###############################################################
#  Generated by:      Cadence Innovus 21.14-s109_1
#  OS:                Linux x86_64(Host ID caen-vnc-mi02.engin.umich.edu)
#  Generated on:      Mon Mar 27 17:20:06 2023
#  Design:            wb_controller
#  Command:           write_lef_abstract /afs/umich.edu/class/eecs627/w23/students/yihengfu/HW2/apr/data/wb_controller.lef -specifyTopLayer 4 -stripePin -PGpinLayers 4
###############################################################

VERSION 5.8 ;

BUSBITCHARS "[]" ;
DIVIDERCHAR "/" ;

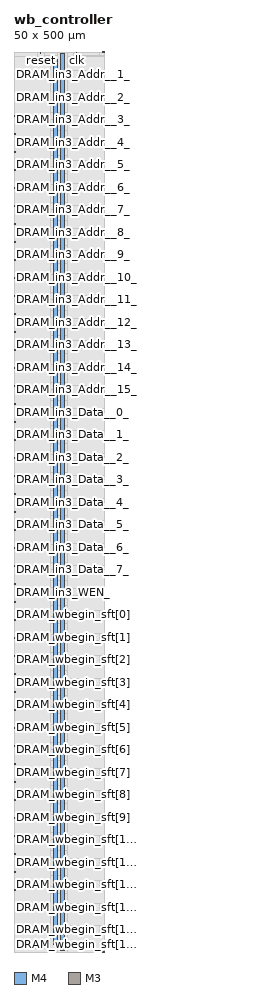
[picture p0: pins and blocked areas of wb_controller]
MACRO wb_controller
  CLASS BLOCK ;
  SIZE 50.000000 BY 500.000000 ;
  FOREIGN wb_controller 0.000000 0.000000 ;
  ORIGIN 0 0 ;
  SYMMETRY X Y R90 ;
  PIN clk
    DIRECTION INPUT ;
    USE SIGNAL ;
    ANTENNAPARTIALMETALAREA 17.54 LAYER M4  ;
    ANTENNAPARTIALMETALSIDEAREA 0.1766 LAYER M4  ;
    ANTENNAMODEL OXIDE1 ;
    ANTENNAGATEAREA 1.2696 LAYER M4  ;
    ANTENNAMAXAREACAR 90.5344 LAYER M4  ;
    ANTENNAMAXSIDEAREACAR 0.914602 LAYER M4  ;
    ANTENNAMAXCUTCAR 3.47643 LAYER V4  ;
    PORT
      LAYER M4 ;
        RECT 34.700000 499.400000 34.900000 500.000000 ;
    END
  END clk
  PIN reset
    DIRECTION INPUT ;
    USE SIGNAL ;
    ANTENNAPARTIALMETALAREA 20.82 LAYER M4  ;
    ANTENNAPARTIALMETALSIDEAREA 0.2094 LAYER M4  ;
    ANTENNAMODEL OXIDE1 ;
    ANTENNAGATEAREA 3.672 LAYER M4  ;
    ANTENNAMAXAREACAR 40.8088 LAYER M4  ;
    ANTENNAMAXSIDEAREACAR 0.411656 LAYER M4  ;
    ANTENNAMAXCUTCAR 1.46605 LAYER V4  ;
    PORT
      LAYER M4 ;
        RECT 14.700000 499.400000 14.900000 500.000000 ;
    END
  END reset
  PIN DRAM_wbegin_sft[15]
    DIRECTION INPUT ;
    USE SIGNAL ;
    ANTENNAPARTIALMETALAREA 0.16 LAYER M4  ;
    ANTENNAPARTIALMETALSIDEAREA 0.0016 LAYER M4  ;
    ANTENNAMODEL OXIDE1 ;
    ANTENNAGATEAREA 0.1728 LAYER M4  ;
    ANTENNAMAXAREACAR 42.2083 LAYER M4  ;
    ANTENNAMAXSIDEAREACAR 0.435532 LAYER M4  ;
    ANTENNAMAXCUTCAR 1.38889 LAYER V4  ;
    PORT
      LAYER M4 ;
        RECT 49.400000 -0.100000 50.000000 0.100000 ;
    END
  END DRAM_wbegin_sft[15]
  PIN DRAM_wbegin_sft[14]
    DIRECTION INPUT ;
    USE SIGNAL ;
    ANTENNAPARTIALMETALAREA 19.26 LAYER M4  ;
    ANTENNAPARTIALMETALSIDEAREA 0.1934 LAYER M4  ;
    ANTENNAMODEL OXIDE1 ;
    ANTENNAGATEAREA 0.1728 LAYER M4  ;
    ANTENNAMAXAREACAR 134.685 LAYER M4  ;
    ANTENNAMAXSIDEAREACAR 1.35567 LAYER M4  ;
    ANTENNAMAXCUTCAR 0.925926 LAYER V4  ;
    PORT
      LAYER M4 ;
        RECT 49.400000 12.400000 50.000000 12.600000 ;
    END
  END DRAM_wbegin_sft[14]
  PIN DRAM_wbegin_sft[13]
    DIRECTION INPUT ;
    USE SIGNAL ;
    ANTENNAPARTIALMETALAREA 0.2 LAYER M4  ;
    ANTENNAPARTIALMETALSIDEAREA 0.002 LAYER M4  ;
    ANTENNAMODEL OXIDE1 ;
    ANTENNAGATEAREA 0.1728 LAYER M4  ;
    ANTENNAMAXAREACAR 37.1157 LAYER M4  ;
    ANTENNAMAXSIDEAREACAR 0.386921 LAYER M4  ;
    ANTENNAMAXCUTCAR 1.38889 LAYER V4  ;
    PORT
      LAYER M4 ;
        RECT 49.400000 24.900000 50.000000 25.100000 ;
    END
  END DRAM_wbegin_sft[13]
  PIN DRAM_wbegin_sft[12]
    DIRECTION INPUT ;
    USE SIGNAL ;
    ANTENNAPARTIALMETALAREA 0.18 LAYER M4  ;
    ANTENNAPARTIALMETALSIDEAREA 0.0018 LAYER M4  ;
    ANTENNAMODEL OXIDE1 ;
    ANTENNAGATEAREA 0.1728 LAYER M4  ;
    ANTENNAMAXAREACAR 61.0741 LAYER M4  ;
    ANTENNAMAXSIDEAREACAR 0.626505 LAYER M4  ;
    ANTENNAMAXCUTCAR 1.38889 LAYER V4  ;
    PORT
      LAYER M4 ;
        RECT 49.400000 37.400000 50.000000 37.600000 ;
    END
  END DRAM_wbegin_sft[12]
  PIN DRAM_wbegin_sft[11]
    DIRECTION INPUT ;
    USE SIGNAL ;
    ANTENNAPARTIALMETALAREA 0.16 LAYER M4  ;
    ANTENNAPARTIALMETALSIDEAREA 0.0016 LAYER M4  ;
    ANTENNAMODEL OXIDE1 ;
    ANTENNAGATEAREA 0.1728 LAYER M4  ;
    ANTENNAMAXAREACAR 35.2639 LAYER M4  ;
    ANTENNAMAXSIDEAREACAR 0.366088 LAYER M4  ;
    ANTENNAMAXCUTCAR 1.38889 LAYER V4  ;
    PORT
      LAYER M4 ;
        RECT 49.400000 49.900000 50.000000 50.100000 ;
    END
  END DRAM_wbegin_sft[11]
  PIN DRAM_wbegin_sft[10]
    DIRECTION INPUT ;
    USE SIGNAL ;
    ANTENNAPARTIALMETALAREA 0.46 LAYER M4  ;
    ANTENNAPARTIALMETALSIDEAREA 0.0046 LAYER M4  ;
    ANTENNAMODEL OXIDE1 ;
    ANTENNAGATEAREA 0.1728 LAYER M4  ;
    ANTENNAMAXAREACAR 47.4167 LAYER M4  ;
    ANTENNAMAXSIDEAREACAR 0.489931 LAYER M4  ;
    ANTENNAMAXCUTCAR 1.38889 LAYER V4  ;
    PORT
      LAYER M4 ;
        RECT 49.400000 62.400000 50.000000 62.600000 ;
    END
  END DRAM_wbegin_sft[10]
  PIN DRAM_wbegin_sft[9]
    DIRECTION INPUT ;
    USE SIGNAL ;
    ANTENNAPARTIALMETALAREA 0.2 LAYER M4  ;
    ANTENNAPARTIALMETALSIDEAREA 0.002 LAYER M4  ;
    ANTENNAMODEL OXIDE1 ;
    ANTENNAGATEAREA 0.1728 LAYER M4  ;
    ANTENNAMAXAREACAR 91.9769 LAYER M4  ;
    ANTENNAMAXSIDEAREACAR 0.937847 LAYER M4  ;
    ANTENNAMAXCUTCAR 1.38889 LAYER V4  ;
    PORT
      LAYER M4 ;
        RECT 49.400000 74.900000 50.000000 75.100000 ;
    END
  END DRAM_wbegin_sft[9]
  PIN DRAM_wbegin_sft[8]
    DIRECTION INPUT ;
    USE SIGNAL ;
    ANTENNAPARTIALMETALAREA 24.54 LAYER M4  ;
    ANTENNAPARTIALMETALSIDEAREA 0.2466 LAYER M4  ;
    ANTENNAMODEL OXIDE1 ;
    ANTENNAGATEAREA 0.1728 LAYER M4  ;
    ANTENNAMAXAREACAR 277.278 LAYER M4  ;
    ANTENNAMAXSIDEAREACAR 2.78391 LAYER M4  ;
    ANTENNAMAXCUTCAR 0.925926 LAYER V4  ;
    PORT
      LAYER M4 ;
        RECT 49.400000 87.400000 50.000000 87.600000 ;
    END
  END DRAM_wbegin_sft[8]
  PIN DRAM_wbegin_sft[7]
    DIRECTION INPUT ;
    USE SIGNAL ;
    ANTENNAPARTIALMETALAREA 0.16 LAYER M4  ;
    ANTENNAPARTIALMETALSIDEAREA 0.0016 LAYER M4  ;
    ANTENNAMODEL OXIDE1 ;
    ANTENNAGATEAREA 0.1728 LAYER M4  ;
    ANTENNAMAXAREACAR 72.7639 LAYER M4  ;
    ANTENNAMAXSIDEAREACAR 0.741088 LAYER M4  ;
    ANTENNAMAXCUTCAR 1.38889 LAYER V4  ;
    PORT
      LAYER M4 ;
        RECT 49.400000 99.900000 50.000000 100.100000 ;
    END
  END DRAM_wbegin_sft[7]
  PIN DRAM_wbegin_sft[6]
    DIRECTION INPUT ;
    USE SIGNAL ;
    ANTENNAPARTIALMETALAREA 0.14 LAYER M4  ;
    ANTENNAPARTIALMETALSIDEAREA 0.0014 LAYER M4  ;
    ANTENNAMODEL OXIDE1 ;
    ANTENNAGATEAREA 0.1728 LAYER M4  ;
    ANTENNAMAXAREACAR 41.8611 LAYER M4  ;
    ANTENNAMAXSIDEAREACAR 0.429745 LAYER M4  ;
    ANTENNAMAXCUTCAR 1.38889 LAYER V4  ;
    PORT
      LAYER M4 ;
        RECT 49.400000 112.400000 50.000000 112.600000 ;
    END
  END DRAM_wbegin_sft[6]
  PIN DRAM_wbegin_sft[5]
    DIRECTION INPUT ;
    USE SIGNAL ;
    ANTENNAPARTIALMETALAREA 0.2 LAYER M4  ;
    ANTENNAPARTIALMETALSIDEAREA 0.002 LAYER M4  ;
    ANTENNAMODEL OXIDE1 ;
    ANTENNAGATEAREA 0.1728 LAYER M4  ;
    ANTENNAMAXAREACAR 34.338 LAYER M4  ;
    ANTENNAMAXSIDEAREACAR 0.359144 LAYER M4  ;
    ANTENNAMAXCUTCAR 1.38889 LAYER V4  ;
    PORT
      LAYER M4 ;
        RECT 49.400000 124.900000 50.000000 125.100000 ;
    END
  END DRAM_wbegin_sft[5]
  PIN DRAM_wbegin_sft[4]
    DIRECTION INPUT ;
    USE SIGNAL ;
    ANTENNAPARTIALMETALAREA 0.18 LAYER M4  ;
    ANTENNAPARTIALMETALSIDEAREA 0.0018 LAYER M4  ;
    ANTENNAMODEL OXIDE1 ;
    ANTENNAGATEAREA 0.1728 LAYER M4  ;
    ANTENNAMAXAREACAR 51.3519 LAYER M4  ;
    ANTENNAMAXSIDEAREACAR 0.529282 LAYER M4  ;
    ANTENNAMAXCUTCAR 1.38889 LAYER V4  ;
    PORT
      LAYER M4 ;
        RECT 49.400000 137.400000 50.000000 137.600000 ;
    END
  END DRAM_wbegin_sft[4]
  PIN DRAM_wbegin_sft[3]
    DIRECTION INPUT ;
    USE SIGNAL ;
    ANTENNAPARTIALMETALAREA 0.48 LAYER M4  ;
    ANTENNAPARTIALMETALSIDEAREA 0.0048 LAYER M4  ;
    ANTENNAMODEL OXIDE1 ;
    ANTENNAGATEAREA 0.1728 LAYER M4  ;
    ANTENNAMAXAREACAR 29.9398 LAYER M4  ;
    ANTENNAMAXSIDEAREACAR 0.305903 LAYER M4  ;
    ANTENNAMAXCUTCAR 1.38889 LAYER V4  ;
    PORT
      LAYER M4 ;
        RECT 49.400000 149.900000 50.000000 150.100000 ;
    END
  END DRAM_wbegin_sft[3]
  PIN DRAM_wbegin_sft[2]
    DIRECTION INPUT ;
    USE SIGNAL ;
    ANTENNAPARTIALMETALAREA 0.14 LAYER M4  ;
    ANTENNAPARTIALMETALSIDEAREA 0.0014 LAYER M4  ;
    ANTENNAMODEL OXIDE1 ;
    ANTENNAGATEAREA 0.1728 LAYER M4  ;
    ANTENNAMAXAREACAR 35.8426 LAYER M4  ;
    ANTENNAMAXSIDEAREACAR 0.36956 LAYER M4  ;
    ANTENNAMAXCUTCAR 1.38889 LAYER V4  ;
    PORT
      LAYER M4 ;
        RECT 49.400000 162.400000 50.000000 162.600000 ;
    END
  END DRAM_wbegin_sft[2]
  PIN DRAM_wbegin_sft[1]
    DIRECTION INPUT ;
    USE SIGNAL ;
    ANTENNAPARTIALMETALAREA 0.2 LAYER M4  ;
    ANTENNAPARTIALMETALSIDEAREA 0.002 LAYER M4  ;
    ANTENNAMODEL OXIDE1 ;
    ANTENNAGATEAREA 0.1728 LAYER M4  ;
    ANTENNAMAXAREACAR 34.338 LAYER M4  ;
    ANTENNAMAXSIDEAREACAR 0.354514 LAYER M4  ;
    ANTENNAMAXCUTCAR 1.38889 LAYER V4  ;
    PORT
      LAYER M4 ;
        RECT 49.400000 174.900000 50.000000 175.100000 ;
    END
  END DRAM_wbegin_sft[1]
  PIN DRAM_wbegin_sft[0]
    DIRECTION INPUT ;
    USE SIGNAL ;
    ANTENNAPARTIALMETALAREA 2.02 LAYER M4  ;
    ANTENNAPARTIALMETALSIDEAREA 0.0202 LAYER M4  ;
    ANTENNAMODEL OXIDE1 ;
    ANTENNAGATEAREA 0.1728 LAYER M4  ;
    ANTENNAMAXAREACAR 65.7778 LAYER M4  ;
    ANTENNAMAXSIDEAREACAR 0.673032 LAYER M4  ;
    ANTENNAMAXCUTCAR 1.15741 LAYER V4  ;
    PORT
      LAYER M4 ;
        RECT 49.400000 187.400000 50.000000 187.600000 ;
    END
  END DRAM_wbegin_sft[0]
  PIN pk_out_3__PE_state__2_
    DIRECTION INPUT ;
    USE SIGNAL ;
    PORT
      LAYER M3 ;
        RECT 0.000000 464.320000 0.760000 464.480000 ;
    END
  END pk_out_3__PE_state__2_
  PIN pk_out_3__PE_state__1_
    DIRECTION INPUT ;
    USE SIGNAL ;
    PORT
      LAYER M3 ;
        RECT 0.000000 454.320000 0.760000 454.480000 ;
    END
  END pk_out_3__PE_state__1_
  PIN pk_out_3__PE_state__0_
    DIRECTION INPUT ;
    USE SIGNAL ;
    PORT
      LAYER M3 ;
        RECT 0.000000 444.320000 0.760000 444.480000 ;
    END
  END pk_out_3__PE_state__0_
  PIN pk_out_3__data__7_
    DIRECTION INPUT ;
    USE SIGNAL ;
    PORT
      LAYER M3 ;
        RECT 0.000000 434.320000 0.760000 434.480000 ;
    END
  END pk_out_3__data__7_
  PIN pk_out_3__data__6_
    DIRECTION INPUT ;
    USE SIGNAL ;
    PORT
      LAYER M3 ;
        RECT 0.000000 424.320000 0.760000 424.480000 ;
    END
  END pk_out_3__data__6_
  PIN pk_out_3__data__5_
    DIRECTION INPUT ;
    USE SIGNAL ;
    PORT
      LAYER M3 ;
        RECT 0.000000 414.320000 0.760000 414.480000 ;
    END
  END pk_out_3__data__5_
  PIN pk_out_3__data__4_
    DIRECTION INPUT ;
    USE SIGNAL ;
    PORT
      LAYER M3 ;
        RECT 0.000000 404.320000 0.760000 404.480000 ;
    END
  END pk_out_3__data__4_
  PIN pk_out_3__data__3_
    DIRECTION INPUT ;
    USE SIGNAL ;
    PORT
      LAYER M3 ;
        RECT 0.000000 394.320000 0.760000 394.480000 ;
    END
  END pk_out_3__data__3_
  PIN pk_out_3__data__2_
    DIRECTION INPUT ;
    USE SIGNAL ;
    PORT
      LAYER M3 ;
        RECT 0.000000 384.320000 0.760000 384.480000 ;
    END
  END pk_out_3__data__2_
  PIN pk_out_3__data__1_
    DIRECTION INPUT ;
    USE SIGNAL ;
    PORT
      LAYER M3 ;
        RECT 0.000000 374.320000 0.760000 374.480000 ;
    END
  END pk_out_3__data__1_
  PIN pk_out_3__data__0_
    DIRECTION INPUT ;
    USE SIGNAL ;
    PORT
      LAYER M3 ;
        RECT 0.000000 364.320000 0.760000 364.480000 ;
    END
  END pk_out_3__data__0_
  PIN pk_out_2__PE_state__2_
    DIRECTION INPUT ;
    USE SIGNAL ;
    PORT
      LAYER M3 ;
        RECT 0.000000 354.320000 0.760000 354.480000 ;
    END
  END pk_out_2__PE_state__2_
  PIN pk_out_2__PE_state__1_
    DIRECTION INPUT ;
    USE SIGNAL ;
    PORT
      LAYER M3 ;
        RECT 0.000000 344.320000 0.760000 344.480000 ;
    END
  END pk_out_2__PE_state__1_
  PIN pk_out_2__PE_state__0_
    DIRECTION INPUT ;
    USE SIGNAL ;
    PORT
      LAYER M3 ;
        RECT 0.000000 334.320000 0.760000 334.480000 ;
    END
  END pk_out_2__PE_state__0_
  PIN pk_out_2__data__7_
    DIRECTION INPUT ;
    USE SIGNAL ;
    PORT
      LAYER M3 ;
        RECT 0.000000 324.320000 0.760000 324.480000 ;
    END
  END pk_out_2__data__7_
  PIN pk_out_2__data__6_
    DIRECTION INPUT ;
    USE SIGNAL ;
    PORT
      LAYER M3 ;
        RECT 0.000000 314.320000 0.760000 314.480000 ;
    END
  END pk_out_2__data__6_
  PIN pk_out_2__data__5_
    DIRECTION INPUT ;
    USE SIGNAL ;
    PORT
      LAYER M3 ;
        RECT 0.000000 304.320000 0.760000 304.480000 ;
    END
  END pk_out_2__data__5_
  PIN pk_out_2__data__4_
    DIRECTION INPUT ;
    USE SIGNAL ;
    PORT
      LAYER M3 ;
        RECT 0.000000 294.320000 0.760000 294.480000 ;
    END
  END pk_out_2__data__4_
  PIN pk_out_2__data__3_
    DIRECTION INPUT ;
    USE SIGNAL ;
    PORT
      LAYER M3 ;
        RECT 0.000000 284.320000 0.760000 284.480000 ;
    END
  END pk_out_2__data__3_
  PIN pk_out_2__data__2_
    DIRECTION INPUT ;
    USE SIGNAL ;
    PORT
      LAYER M3 ;
        RECT 0.000000 274.320000 0.760000 274.480000 ;
    END
  END pk_out_2__data__2_
  PIN pk_out_2__data__1_
    DIRECTION INPUT ;
    USE SIGNAL ;
    PORT
      LAYER M3 ;
        RECT 0.000000 264.320000 0.760000 264.480000 ;
    END
  END pk_out_2__data__1_
  PIN pk_out_2__data__0_
    DIRECTION INPUT ;
    USE SIGNAL ;
    PORT
      LAYER M3 ;
        RECT 0.000000 254.320000 0.760000 254.480000 ;
    END
  END pk_out_2__data__0_
  PIN pk_out_1__PE_state__2_
    DIRECTION INPUT ;
    USE SIGNAL ;
    PORT
      LAYER M3 ;
        RECT 0.000000 244.320000 0.760000 244.480000 ;
    END
  END pk_out_1__PE_state__2_
  PIN pk_out_1__PE_state__1_
    DIRECTION INPUT ;
    USE SIGNAL ;
    PORT
      LAYER M3 ;
        RECT 0.000000 234.320000 0.760000 234.480000 ;
    END
  END pk_out_1__PE_state__1_
  PIN pk_out_1__PE_state__0_
    DIRECTION INPUT ;
    USE SIGNAL ;
    PORT
      LAYER M3 ;
        RECT 0.000000 224.320000 0.760000 224.480000 ;
    END
  END pk_out_1__PE_state__0_
  PIN pk_out_1__data__7_
    DIRECTION INPUT ;
    USE SIGNAL ;
    PORT
      LAYER M3 ;
        RECT 0.000000 214.320000 0.760000 214.480000 ;
    END
  END pk_out_1__data__7_
  PIN pk_out_1__data__6_
    DIRECTION INPUT ;
    USE SIGNAL ;
    PORT
      LAYER M3 ;
        RECT 0.000000 204.320000 0.760000 204.480000 ;
    END
  END pk_out_1__data__6_
  PIN pk_out_1__data__5_
    DIRECTION INPUT ;
    USE SIGNAL ;
    PORT
      LAYER M3 ;
        RECT 0.000000 194.320000 0.760000 194.480000 ;
    END
  END pk_out_1__data__5_
  PIN pk_out_1__data__4_
    DIRECTION INPUT ;
    USE SIGNAL ;
    PORT
      LAYER M3 ;
        RECT 0.000000 184.320000 0.760000 184.480000 ;
    END
  END pk_out_1__data__4_
  PIN pk_out_1__data__3_
    DIRECTION INPUT ;
    USE SIGNAL ;
    PORT
      LAYER M3 ;
        RECT 0.000000 174.320000 0.760000 174.480000 ;
    END
  END pk_out_1__data__3_
  PIN pk_out_1__data__2_
    DIRECTION INPUT ;
    USE SIGNAL ;
    PORT
      LAYER M3 ;
        RECT 0.000000 164.320000 0.760000 164.480000 ;
    END
  END pk_out_1__data__2_
  PIN pk_out_1__data__1_
    DIRECTION INPUT ;
    USE SIGNAL ;
    PORT
      LAYER M3 ;
        RECT 0.000000 154.320000 0.760000 154.480000 ;
    END
  END pk_out_1__data__1_
  PIN pk_out_1__data__0_
    DIRECTION INPUT ;
    USE SIGNAL ;
    PORT
      LAYER M3 ;
        RECT 0.000000 144.320000 0.760000 144.480000 ;
    END
  END pk_out_1__data__0_
  PIN pk_out_0__PE_state__2_
    DIRECTION INPUT ;
    USE SIGNAL ;
    ANTENNAPARTIALMETALAREA 2.9224 LAYER M3  ;
    ANTENNAPARTIALMETALSIDEAREA 0.02916 LAYER M3  ;
    ANTENNAMODEL OXIDE1 ;
    ANTENNAGATEAREA 0.312 LAYER M3  ;
    ANTENNAMAXAREACAR 10.0538 LAYER M3  ;
    ANTENNAMAXSIDEAREACAR 0.102692 LAYER M3  ;
    ANTENNAMAXCUTCAR 0.25641 LAYER V3  ;
    PORT
      LAYER M3 ;
        RECT 0.000000 134.320000 0.760000 134.480000 ;
    END
  END pk_out_0__PE_state__2_
  PIN pk_out_0__PE_state__1_
    DIRECTION INPUT ;
    USE SIGNAL ;
    ANTENNAPARTIALMETALAREA 2.7624 LAYER M3  ;
    ANTENNAPARTIALMETALSIDEAREA 0.02756 LAYER M3  ;
    ANTENNAMODEL OXIDE1 ;
    ANTENNAGATEAREA 0.1488 LAYER M3  ;
    ANTENNAMAXAREACAR 20.3918 LAYER M3  ;
    ANTENNAMAXSIDEAREACAR 0.20672 LAYER M3  ;
    ANTENNAMAXCUTCAR 0.537634 LAYER V3  ;
    PORT
      LAYER M3 ;
        RECT 0.000000 124.320000 0.760000 124.480000 ;
    END
  END pk_out_0__PE_state__1_
  PIN pk_out_0__PE_state__0_
    DIRECTION INPUT ;
    USE SIGNAL ;
    ANTENNAPARTIALMETALAREA 2.2824 LAYER M3  ;
    ANTENNAPARTIALMETALSIDEAREA 0.02276 LAYER M3  ;
    ANTENNAMODEL OXIDE1 ;
    ANTENNAGATEAREA 0.1488 LAYER M3  ;
    ANTENNAMAXAREACAR 31.584 LAYER M3  ;
    ANTENNAMAXSIDEAREACAR 0.31707 LAYER M3  ;
    ANTENNAMAXCUTCAR 0.537634 LAYER V3  ;
    PORT
      LAYER M3 ;
        RECT 0.000000 114.320000 0.760000 114.480000 ;
    END
  END pk_out_0__PE_state__0_
  PIN pk_out_0__data__7_
    DIRECTION INPUT ;
    USE SIGNAL ;
    ANTENNAPARTIALMETALAREA 6.1624 LAYER M3  ;
    ANTENNAPARTIALMETALSIDEAREA 0.06196 LAYER M3  ;
    ANTENNAMODEL OXIDE1 ;
    ANTENNAGATEAREA 0.1728 LAYER M3  ;
    ANTENNAMAXAREACAR 37.6667 LAYER M3  ;
    ANTENNAMAXSIDEAREACAR 0.382292 LAYER M3  ;
    ANTENNAMAXCUTCAR 0.462963 LAYER V3  ;
    PORT
      LAYER M3 ;
        RECT 0.000000 104.320000 0.760000 104.480000 ;
    END
  END pk_out_0__data__7_
  PIN pk_out_0__data__6_
    DIRECTION INPUT ;
    USE SIGNAL ;
    ANTENNAPARTIALMETALAREA 6.8024 LAYER M3  ;
    ANTENNAPARTIALMETALSIDEAREA 0.06836 LAYER M3  ;
    ANTENNAMODEL OXIDE1 ;
    ANTENNAGATEAREA 0.1728 LAYER M3  ;
    ANTENNAMAXAREACAR 40.9074 LAYER M3  ;
    ANTENNAMAXSIDEAREACAR 0.414699 LAYER M3  ;
    ANTENNAMAXCUTCAR 0.694444 LAYER V3  ;
    PORT
      LAYER M3 ;
        RECT 0.000000 94.320000 0.760000 94.480000 ;
    END
  END pk_out_0__data__6_
  PIN pk_out_0__data__5_
    DIRECTION INPUT ;
    USE SIGNAL ;
    ANTENNAPARTIALMETALAREA 6.4024 LAYER M3  ;
    ANTENNAPARTIALMETALSIDEAREA 0.06436 LAYER M3  ;
    ANTENNAMODEL OXIDE1 ;
    ANTENNAGATEAREA 0.1728 LAYER M3  ;
    ANTENNAMAXAREACAR 40.4444 LAYER M3  ;
    ANTENNAMAXSIDEAREACAR 0.410069 LAYER M3  ;
    ANTENNAMAXCUTCAR 0.694444 LAYER V3  ;
    PORT
      LAYER M3 ;
        RECT 0.000000 84.320000 0.760000 84.480000 ;
    END
  END pk_out_0__data__5_
  PIN pk_out_0__data__4_
    DIRECTION INPUT ;
    USE SIGNAL ;
    ANTENNAPARTIALMETALAREA 6.1624 LAYER M3  ;
    ANTENNAPARTIALMETALSIDEAREA 0.06196 LAYER M3  ;
    ANTENNAPARTIALCUTAREA 0.08 LAYER V3  ;
    ANTENNAPARTIALMETALAREA 1.8 LAYER M4  ;
    ANTENNAPARTIALMETALSIDEAREA 0.0184 LAYER M4  ;
    ANTENNAMODEL OXIDE1 ;
    ANTENNAGATEAREA 0.1728 LAYER M4  ;
    ANTENNAMAXAREACAR 14.0417 LAYER M4  ;
    ANTENNAMAXSIDEAREACAR 0.148727 LAYER M4  ;
    ANTENNAMAXCUTCAR 1.15741 LAYER V4  ;
    PORT
      LAYER M3 ;
        RECT 0.000000 74.320000 0.760000 74.480000 ;
    END
  END pk_out_0__data__4_
  PIN pk_out_0__data__3_
    DIRECTION INPUT ;
    USE SIGNAL ;
    ANTENNAPARTIALMETALAREA 5.0824 LAYER M3  ;
    ANTENNAPARTIALMETALSIDEAREA 0.05076 LAYER M3  ;
    ANTENNAMODEL OXIDE1 ;
    ANTENNAGATEAREA 0.1728 LAYER M3  ;
    ANTENNAMAXAREACAR 168.454 LAYER M3  ;
    ANTENNAMAXSIDEAREACAR 1.68785 LAYER M3  ;
    ANTENNAMAXCUTCAR 0.694444 LAYER V3  ;
    PORT
      LAYER M3 ;
        RECT 0.000000 64.320000 0.760000 64.480000 ;
    END
  END pk_out_0__data__3_
  PIN pk_out_0__data__2_
    DIRECTION INPUT ;
    USE SIGNAL ;
    ANTENNAPARTIALMETALAREA 2.5224 LAYER M3  ;
    ANTENNAPARTIALMETALSIDEAREA 0.02516 LAYER M3  ;
    ANTENNAMODEL OXIDE1 ;
    ANTENNAGATEAREA 0.1728 LAYER M3  ;
    ANTENNAMAXAREACAR 148.083 LAYER M3  ;
    ANTENNAMAXSIDEAREACAR 1.48414 LAYER M3  ;
    ANTENNAMAXCUTCAR 0.694444 LAYER V3  ;
    PORT
      LAYER M3 ;
        RECT 0.000000 54.320000 0.760000 54.480000 ;
    END
  END pk_out_0__data__2_
  PIN pk_out_0__data__1_
    DIRECTION INPUT ;
    USE SIGNAL ;
    ANTENNAPARTIALMETALAREA 5.9624 LAYER M3  ;
    ANTENNAPARTIALMETALSIDEAREA 0.05956 LAYER M3  ;
    ANTENNAMODEL OXIDE1 ;
    ANTENNAGATEAREA 0.1728 LAYER M3  ;
    ANTENNAMAXAREACAR 173.546 LAYER M3  ;
    ANTENNAMAXSIDEAREACAR 1.73877 LAYER M3  ;
    ANTENNAMAXCUTCAR 0.694444 LAYER V3  ;
    PORT
      LAYER M3 ;
        RECT 0.000000 44.320000 0.760000 44.480000 ;
    END
  END pk_out_0__data__1_
  PIN pk_out_0__data__0_
    DIRECTION INPUT ;
    USE SIGNAL ;
    ANTENNAPARTIALMETALAREA 2.9624 LAYER M3  ;
    ANTENNAPARTIALMETALSIDEAREA 0.02996 LAYER M3  ;
    ANTENNAPARTIALCUTAREA 0.08 LAYER V3  ;
    ANTENNAPARTIALMETALAREA 0.76 LAYER M4  ;
    ANTENNAPARTIALMETALSIDEAREA 0.008 LAYER M4  ;
    ANTENNAMODEL OXIDE1 ;
    ANTENNAGATEAREA 0.1728 LAYER M4  ;
    ANTENNAMAXAREACAR 13.1157 LAYER M4  ;
    ANTENNAMAXSIDEAREACAR 0.139468 LAYER M4  ;
    ANTENNAMAXCUTCAR 1.15741 LAYER V4  ;
    PORT
      LAYER M3 ;
        RECT 0.000000 34.320000 0.760000 34.480000 ;
    END
  END pk_out_0__data__0_
  PIN DRAM_in3_Data__7_
    DIRECTION OUTPUT ;
    USE SIGNAL ;
    ANTENNADIFFAREA 2.112 LAYER M4  ;
    ANTENNAPARTIALMETALAREA 5 LAYER M4  ;
    ANTENNAPARTIALMETALSIDEAREA 0.0504 LAYER M4  ;
    PORT
      LAYER M4 ;
        RECT 49.400000 212.400000 50.000000 212.600000 ;
    END
  END DRAM_in3_Data__7_
  PIN DRAM_in3_Data__6_
    DIRECTION OUTPUT ;
    USE SIGNAL ;
    ANTENNADIFFAREA 2.112 LAYER M4  ;
    ANTENNAPARTIALMETALAREA 1.72 LAYER M4  ;
    ANTENNAPARTIALMETALSIDEAREA 0.0172 LAYER M4  ;
    PORT
      LAYER M4 ;
        RECT 49.400000 224.900000 50.000000 225.100000 ;
    END
  END DRAM_in3_Data__6_
  PIN DRAM_in3_Data__5_
    DIRECTION OUTPUT ;
    USE SIGNAL ;
    ANTENNADIFFAREA 2.112 LAYER M4  ;
    ANTENNAPARTIALMETALAREA 0.14 LAYER M4  ;
    ANTENNAPARTIALMETALSIDEAREA 0.0014 LAYER M4  ;
    PORT
      LAYER M4 ;
        RECT 49.400000 237.400000 50.000000 237.600000 ;
    END
  END DRAM_in3_Data__5_
  PIN DRAM_in3_Data__4_
    DIRECTION OUTPUT ;
    USE SIGNAL ;
    ANTENNADIFFAREA 2.112 LAYER M4  ;
    ANTENNAPARTIALMETALAREA 6.12 LAYER M4  ;
    ANTENNAPARTIALMETALSIDEAREA 0.0616 LAYER M4  ;
    PORT
      LAYER M4 ;
        RECT 49.400000 249.900000 50.000000 250.100000 ;
    END
  END DRAM_in3_Data__4_
  PIN DRAM_in3_Data__3_
    DIRECTION OUTPUT ;
    USE SIGNAL ;
    ANTENNADIFFAREA 2.112 LAYER M4  ;
    ANTENNAPARTIALMETALAREA 15.64 LAYER M4  ;
    ANTENNAPARTIALMETALSIDEAREA 0.1568 LAYER M4  ;
    PORT
      LAYER M4 ;
        RECT 49.400000 262.400000 50.000000 262.600000 ;
    END
  END DRAM_in3_Data__3_
  PIN DRAM_in3_Data__2_
    DIRECTION OUTPUT ;
    USE SIGNAL ;
    ANTENNADIFFAREA 2.112 LAYER M4  ;
    ANTENNAPARTIALMETALAREA 0.36 LAYER M4  ;
    ANTENNAPARTIALMETALSIDEAREA 0.0036 LAYER M4  ;
    PORT
      LAYER M4 ;
        RECT 49.400000 274.900000 50.000000 275.100000 ;
    END
  END DRAM_in3_Data__2_
  PIN DRAM_in3_Data__1_
    DIRECTION OUTPUT ;
    USE SIGNAL ;
    ANTENNADIFFAREA 2.112 LAYER M4  ;
    ANTENNAPARTIALMETALAREA 14.5 LAYER M4  ;
    ANTENNAPARTIALMETALSIDEAREA 0.1454 LAYER M4  ;
    PORT
      LAYER M4 ;
        RECT 49.400000 287.400000 50.000000 287.600000 ;
    END
  END DRAM_in3_Data__1_
  PIN DRAM_in3_Data__0_
    DIRECTION OUTPUT ;
    USE SIGNAL ;
    ANTENNADIFFAREA 2.112 LAYER M4  ;
    ANTENNAPARTIALMETALAREA 0.88 LAYER M4  ;
    ANTENNAPARTIALMETALSIDEAREA 0.0088 LAYER M4  ;
    PORT
      LAYER M4 ;
        RECT 49.400000 299.900000 50.000000 300.100000 ;
    END
  END DRAM_in3_Data__0_
  PIN DRAM_in3_WEN_
    DIRECTION OUTPUT ;
    USE SIGNAL ;
    ANTENNADIFFAREA 3.52 LAYER M4  ;
    ANTENNAPARTIALMETALAREA 0.16 LAYER M4  ;
    ANTENNAPARTIALMETALSIDEAREA 0.0016 LAYER M4  ;
    ANTENNAMODEL OXIDE1 ;
    ANTENNAGATEAREA 0.5592 LAYER M4  ;
    ANTENNAMAXAREACAR 73.3623 LAYER M4  ;
    ANTENNAMAXSIDEAREACAR 0.737416 LAYER M4  ;
    ANTENNAMAXCUTCAR 0.952123 LAYER V4  ;
    PORT
      LAYER M4 ;
        RECT 49.400000 199.900000 50.000000 200.100000 ;
    END
  END DRAM_in3_WEN_
  PIN DRAM_in3_Addr__15_
    DIRECTION OUTPUT ;
    USE SIGNAL ;
    ANTENNADIFFAREA 1.728 LAYER M4  ;
    ANTENNAPARTIALMETALAREA 2.26 LAYER M4  ;
    ANTENNAPARTIALMETALSIDEAREA 0.0226 LAYER M4  ;
    PORT
      LAYER M4 ;
        RECT 49.400000 312.400000 50.000000 312.600000 ;
    END
  END DRAM_in3_Addr__15_
  PIN DRAM_in3_Addr__14_
    DIRECTION OUTPUT ;
    USE SIGNAL ;
    ANTENNADIFFAREA 0.996 LAYER M4  ;
    ANTENNAPARTIALMETALAREA 2.36 LAYER M4  ;
    ANTENNAPARTIALMETALSIDEAREA 0.0236 LAYER M4  ;
    ANTENNAMODEL OXIDE1 ;
    ANTENNAGATEAREA 0.0696 LAYER M4  ;
    ANTENNAMAXAREACAR 101.286 LAYER M4  ;
    ANTENNAMAXSIDEAREACAR 1.02644 LAYER M4  ;
    ANTENNAMAXCUTCAR 2.87356 LAYER V4  ;
    PORT
      LAYER M4 ;
        RECT 49.400000 324.900000 50.000000 325.100000 ;
    END
  END DRAM_in3_Addr__14_
  PIN DRAM_in3_Addr__13_
    DIRECTION OUTPUT ;
    USE SIGNAL ;
    ANTENNADIFFAREA 2.014 LAYER M4  ;
    ANTENNAPARTIALMETALAREA 1.82 LAYER M4  ;
    ANTENNAPARTIALMETALSIDEAREA 0.0182 LAYER M4  ;
    ANTENNAMODEL OXIDE1 ;
    ANTENNAGATEAREA 0.3504 LAYER M4  ;
    ANTENNAMAXAREACAR 34.0386 LAYER M4  ;
    ANTENNAMAXSIDEAREACAR 0.349358 LAYER M4  ;
    ANTENNAMAXCUTCAR 1.95245 LAYER V4  ;
    PORT
      LAYER M4 ;
        RECT 49.400000 337.400000 50.000000 337.600000 ;
    END
  END DRAM_in3_Addr__13_
  PIN DRAM_in3_Addr__12_
    DIRECTION OUTPUT ;
    USE SIGNAL ;
    ANTENNADIFFAREA 2.014 LAYER M4  ;
    ANTENNAPARTIALMETALAREA 0.24 LAYER M4  ;
    ANTENNAPARTIALMETALSIDEAREA 0.0024 LAYER M4  ;
    ANTENNAMODEL OXIDE1 ;
    ANTENNAGATEAREA 0.3504 LAYER M4  ;
    ANTENNAMAXAREACAR 27.4436 LAYER M4  ;
    ANTENNAMAXSIDEAREACAR 0.2812 LAYER M4  ;
    ANTENNAMAXCUTCAR 1.95245 LAYER V4  ;
    PORT
      LAYER M4 ;
        RECT 49.400000 349.900000 50.000000 350.100000 ;
    END
  END DRAM_in3_Addr__12_
  PIN DRAM_in3_Addr__11_
    DIRECTION OUTPUT ;
    USE SIGNAL ;
    ANTENNADIFFAREA 3.2 LAYER M4  ;
    ANTENNAPARTIALMETALAREA 2.34 LAYER M4  ;
    ANTENNAPARTIALMETALSIDEAREA 0.0234 LAYER M4  ;
    ANTENNAMODEL OXIDE1 ;
    ANTENNAGATEAREA 0.2184 LAYER M4  ;
    ANTENNAMAXAREACAR 124.006 LAYER M4  ;
    ANTENNAMAXSIDEAREACAR 1.24538 LAYER M4  ;
    ANTENNAMAXCUTCAR 2.09044 LAYER V4  ;
    PORT
      LAYER M4 ;
        RECT 49.400000 362.400000 50.000000 362.600000 ;
    END
  END DRAM_in3_Addr__11_
  PIN DRAM_in3_Addr__10_
    DIRECTION OUTPUT ;
    USE SIGNAL ;
    ANTENNADIFFAREA 2.014 LAYER M4  ;
    ANTENNAPARTIALMETALAREA 5.32 LAYER M4  ;
    ANTENNAPARTIALMETALSIDEAREA 0.0532 LAYER M4  ;
    ANTENNAMODEL OXIDE1 ;
    ANTENNAGATEAREA 0.3504 LAYER M4  ;
    ANTENNAMAXAREACAR 46.7627 LAYER M4  ;
    ANTENNAMAXSIDEAREACAR 0.473364 LAYER M4  ;
    ANTENNAMAXCUTCAR 1.95245 LAYER V4  ;
    PORT
      LAYER M4 ;
        RECT 49.400000 374.900000 50.000000 375.100000 ;
    END
  END DRAM_in3_Addr__10_
  PIN DRAM_in3_Addr__9_
    DIRECTION OUTPUT ;
    USE SIGNAL ;
    ANTENNADIFFAREA 2.014 LAYER M4  ;
    ANTENNAPARTIALMETALAREA 0.46 LAYER M4  ;
    ANTENNAPARTIALMETALSIDEAREA 0.0046 LAYER M4  ;
    ANTENNAMODEL OXIDE1 ;
    ANTENNAGATEAREA 0.3504 LAYER M4  ;
    ANTENNAMAXAREACAR 37.9256 LAYER M4  ;
    ANTENNAMAXSIDEAREACAR 0.38434 LAYER M4  ;
    ANTENNAMAXCUTCAR 1.95245 LAYER V4  ;
    PORT
      LAYER M4 ;
        RECT 49.400000 387.400000 50.000000 387.600000 ;
    END
  END DRAM_in3_Addr__9_
  PIN DRAM_in3_Addr__8_
    DIRECTION OUTPUT ;
    USE SIGNAL ;
    ANTENNADIFFAREA 2.014 LAYER M4  ;
    ANTENNAPARTIALMETALAREA 8.12 LAYER M4  ;
    ANTENNAPARTIALMETALSIDEAREA 0.0816 LAYER M4  ;
    ANTENNAMODEL OXIDE1 ;
    ANTENNAGATEAREA 0.4992 LAYER M4  ;
    ANTENNAMAXAREACAR 49.0778 LAYER M4  ;
    ANTENNAMAXSIDEAREACAR 0.494379 LAYER M4  ;
    ANTENNAMAXCUTCAR 1.88439 LAYER V4  ;
    PORT
      LAYER M4 ;
        RECT 49.400000 399.900000 50.000000 400.100000 ;
    END
  END DRAM_in3_Addr__8_
  PIN DRAM_in3_Addr__7_
    DIRECTION OUTPUT ;
    USE SIGNAL ;
    ANTENNADIFFAREA 2.014 LAYER M4  ;
    ANTENNAPARTIALMETALAREA 1.46 LAYER M4  ;
    ANTENNAPARTIALMETALSIDEAREA 0.0146 LAYER M4  ;
    ANTENNAMODEL OXIDE1 ;
    ANTENNAGATEAREA 0.3504 LAYER M4  ;
    ANTENNAMAXAREACAR 39.8094 LAYER M4  ;
    ANTENNAMAXSIDEAREACAR 0.408207 LAYER M4  ;
    ANTENNAMAXCUTCAR 1.95245 LAYER V4  ;
    PORT
      LAYER M4 ;
        RECT 49.400000 412.400000 50.000000 412.600000 ;
    END
  END DRAM_in3_Addr__7_
  PIN DRAM_in3_Addr__6_
    DIRECTION OUTPUT ;
    USE SIGNAL ;
    ANTENNADIFFAREA 2.014 LAYER M4  ;
    ANTENNAPARTIALMETALAREA 2.36 LAYER M4  ;
    ANTENNAPARTIALMETALSIDEAREA 0.0236 LAYER M4  ;
    ANTENNAMODEL OXIDE1 ;
    ANTENNAGATEAREA 0.4992 LAYER M4  ;
    ANTENNAMAXAREACAR 56.498 LAYER M4  ;
    ANTENNAMAXSIDEAREACAR 0.569815 LAYER M4  ;
    ANTENNAMAXCUTCAR 1.88439 LAYER V4  ;
    PORT
      LAYER M4 ;
        RECT 49.400000 424.900000 50.000000 425.100000 ;
    END
  END DRAM_in3_Addr__6_
  PIN DRAM_in3_Addr__5_
    DIRECTION OUTPUT ;
    USE SIGNAL ;
    ANTENNADIFFAREA 2.014 LAYER M4  ;
    ANTENNAPARTIALMETALAREA 4.02 LAYER M4  ;
    ANTENNAPARTIALMETALSIDEAREA 0.0406 LAYER M4  ;
    ANTENNAMODEL OXIDE1 ;
    ANTENNAGATEAREA 0.3504 LAYER M4  ;
    ANTENNAMAXAREACAR 35.5641 LAYER M4  ;
    ANTENNAMAXSIDEAREACAR 0.36252 LAYER M4  ;
    ANTENNAMAXCUTCAR 1.95245 LAYER V4  ;
    PORT
      LAYER M4 ;
        RECT 49.400000 437.400000 50.000000 437.600000 ;
    END
  END DRAM_in3_Addr__5_
  PIN DRAM_in3_Addr__4_
    DIRECTION OUTPUT ;
    USE SIGNAL ;
    ANTENNADIFFAREA 2.014 LAYER M4  ;
    ANTENNAPARTIALMETALAREA 5.08 LAYER M4  ;
    ANTENNAPARTIALMETALSIDEAREA 0.0512 LAYER M4  ;
    ANTENNAMODEL OXIDE1 ;
    ANTENNAGATEAREA 0.3504 LAYER M4  ;
    ANTENNAMAXAREACAR 45.6569 LAYER M4  ;
    ANTENNAMAXSIDEAREACAR 0.468966 LAYER M4  ;
    ANTENNAMAXCUTCAR 3.10187 LAYER V4  ;
    PORT
      LAYER M4 ;
        RECT 49.400000 449.900000 50.000000 450.100000 ;
    END
  END DRAM_in3_Addr__4_
  PIN DRAM_in3_Addr__3_
    DIRECTION OUTPUT ;
    USE SIGNAL ;
    ANTENNADIFFAREA 2.014 LAYER M4  ;
    ANTENNAPARTIALMETALAREA 0.26 LAYER M4  ;
    ANTENNAPARTIALMETALSIDEAREA 0.0026 LAYER M4  ;
    ANTENNAMODEL OXIDE1 ;
    ANTENNAGATEAREA 0.3504 LAYER M4  ;
    ANTENNAMAXAREACAR 30.274 LAYER M4  ;
    ANTENNAMAXSIDEAREACAR 0.308706 LAYER M4  ;
    ANTENNAMAXCUTCAR 1.53562 LAYER V4  ;
    PORT
      LAYER M4 ;
        RECT 49.400000 462.400000 50.000000 462.600000 ;
    END
  END DRAM_in3_Addr__3_
  PIN DRAM_in3_Addr__2_
    DIRECTION OUTPUT ;
    USE SIGNAL ;
    ANTENNADIFFAREA 2.014 LAYER M4  ;
    ANTENNAPARTIALMETALAREA 0.2 LAYER M4  ;
    ANTENNAPARTIALMETALSIDEAREA 0.002 LAYER M4  ;
    ANTENNAMODEL OXIDE1 ;
    ANTENNAGATEAREA 0.4992 LAYER M4  ;
    ANTENNAMAXAREACAR 42.5216 LAYER M4  ;
    ANTENNAMAXSIDEAREACAR 0.43545 LAYER M4  ;
    ANTENNAMAXCUTCAR 3.03382 LAYER V4  ;
    PORT
      LAYER M4 ;
        RECT 49.400000 474.900000 50.000000 475.100000 ;
    END
  END DRAM_in3_Addr__2_
  PIN DRAM_in3_Addr__1_
    DIRECTION OUTPUT ;
    USE SIGNAL ;
    ANTENNADIFFAREA 2.014 LAYER M4  ;
    ANTENNAPARTIALMETALAREA 2.38 LAYER M4  ;
    ANTENNAPARTIALMETALSIDEAREA 0.0238 LAYER M4  ;
    ANTENNAMODEL OXIDE1 ;
    ANTENNAGATEAREA 0.3504 LAYER M4  ;
    ANTENNAMAXAREACAR 44.6669 LAYER M4  ;
    ANTENNAMAXSIDEAREACAR 0.457924 LAYER M4  ;
    ANTENNAMAXCUTCAR 3.10187 LAYER V4  ;
    PORT
      LAYER M4 ;
        RECT 49.400000 487.400000 50.000000 487.600000 ;
    END
  END DRAM_in3_Addr__1_
  PIN DRAM_in3_Addr__0_
    DIRECTION OUTPUT ;
    USE SIGNAL ;
    ANTENNADIFFAREA 2.176 LAYER M4  ;
    ANTENNAPARTIALMETALAREA 0.16 LAYER M4  ;
    ANTENNAPARTIALMETALSIDEAREA 0.0016 LAYER M4  ;
    ANTENNAMODEL OXIDE1 ;
    ANTENNAGATEAREA 0.648 LAYER M4  ;
    ANTENNAMAXAREACAR 103.759 LAYER M4  ;
    ANTENNAMAXSIDEAREACAR 1.04279 LAYER M4  ;
    ANTENNAMAXCUTCAR 1.73636 LAYER V4  ;
    PORT
      LAYER M4 ;
        RECT 49.400000 499.900000 50.000000 500.100000 ;
    END
  END DRAM_in3_Addr__0_
  PIN VSS
    DIRECTION INOUT ;
    USE GROUND ;

# P/G power stripe data as pin
    PORT
      LAYER M4 ;
        RECT 26.000000 1.000000 28.000000 499.000000 ;
    END
# end of P/G power stripe data as pin

  END VSS
  PIN VDD
    DIRECTION INOUT ;
    USE POWER ;

# P/G power stripe data as pin
    PORT
      LAYER M4 ;
        RECT 22.000000 4.000000 24.000000 496.000000 ;
    END
# end of P/G power stripe data as pin

  END VDD
  OBS
    LAYER M1 ;
      RECT 0.000000 0.000000 50.000000 500.000000 ;
    LAYER M2 ;
      RECT 0.000000 0.000000 50.000000 500.000000 ;
    LAYER M3 ;
      RECT 0.000000 466.400000 50.000000 500.000000 ;
      RECT 2.680000 462.400000 50.000000 466.400000 ;
      RECT 0.000000 456.400000 50.000000 462.400000 ;
      RECT 2.680000 452.400000 50.000000 456.400000 ;
      RECT 0.000000 446.400000 50.000000 452.400000 ;
      RECT 2.680000 442.400000 50.000000 446.400000 ;
      RECT 0.000000 436.400000 50.000000 442.400000 ;
      RECT 2.680000 432.400000 50.000000 436.400000 ;
      RECT 0.000000 426.400000 50.000000 432.400000 ;
      RECT 2.680000 422.400000 50.000000 426.400000 ;
      RECT 0.000000 416.400000 50.000000 422.400000 ;
      RECT 2.680000 412.400000 50.000000 416.400000 ;
      RECT 0.000000 406.400000 50.000000 412.400000 ;
      RECT 2.680000 402.400000 50.000000 406.400000 ;
      RECT 0.000000 396.400000 50.000000 402.400000 ;
      RECT 2.680000 392.400000 50.000000 396.400000 ;
      RECT 0.000000 386.400000 50.000000 392.400000 ;
      RECT 2.680000 382.400000 50.000000 386.400000 ;
      RECT 0.000000 376.400000 50.000000 382.400000 ;
      RECT 2.680000 372.400000 50.000000 376.400000 ;
      RECT 0.000000 366.400000 50.000000 372.400000 ;
      RECT 2.680000 362.400000 50.000000 366.400000 ;
      RECT 0.000000 356.400000 50.000000 362.400000 ;
      RECT 2.680000 352.400000 50.000000 356.400000 ;
      RECT 0.000000 346.400000 50.000000 352.400000 ;
      RECT 2.680000 342.400000 50.000000 346.400000 ;
      RECT 0.000000 336.400000 50.000000 342.400000 ;
      RECT 2.680000 332.400000 50.000000 336.400000 ;
      RECT 0.000000 326.400000 50.000000 332.400000 ;
      RECT 2.680000 322.400000 50.000000 326.400000 ;
      RECT 0.000000 316.400000 50.000000 322.400000 ;
      RECT 2.680000 312.400000 50.000000 316.400000 ;
      RECT 0.000000 306.400000 50.000000 312.400000 ;
      RECT 2.680000 302.400000 50.000000 306.400000 ;
      RECT 0.000000 296.400000 50.000000 302.400000 ;
      RECT 2.680000 292.400000 50.000000 296.400000 ;
      RECT 0.000000 286.400000 50.000000 292.400000 ;
      RECT 2.680000 282.400000 50.000000 286.400000 ;
      RECT 0.000000 276.400000 50.000000 282.400000 ;
      RECT 2.680000 272.400000 50.000000 276.400000 ;
      RECT 0.000000 266.400000 50.000000 272.400000 ;
      RECT 2.680000 262.400000 50.000000 266.400000 ;
      RECT 0.000000 256.400000 50.000000 262.400000 ;
      RECT 2.680000 252.400000 50.000000 256.400000 ;
      RECT 0.000000 246.400000 50.000000 252.400000 ;
      RECT 2.680000 242.400000 50.000000 246.400000 ;
      RECT 0.000000 236.400000 50.000000 242.400000 ;
      RECT 2.680000 232.400000 50.000000 236.400000 ;
      RECT 0.000000 226.400000 50.000000 232.400000 ;
      RECT 2.680000 222.400000 50.000000 226.400000 ;
      RECT 0.000000 216.400000 50.000000 222.400000 ;
      RECT 2.680000 212.400000 50.000000 216.400000 ;
      RECT 0.000000 206.400000 50.000000 212.400000 ;
      RECT 2.680000 202.400000 50.000000 206.400000 ;
      RECT 0.000000 196.400000 50.000000 202.400000 ;
      RECT 2.680000 192.400000 50.000000 196.400000 ;
      RECT 0.000000 186.400000 50.000000 192.400000 ;
      RECT 2.680000 182.400000 50.000000 186.400000 ;
      RECT 0.000000 176.400000 50.000000 182.400000 ;
      RECT 2.680000 172.400000 50.000000 176.400000 ;
      RECT 0.000000 166.400000 50.000000 172.400000 ;
      RECT 2.680000 162.400000 50.000000 166.400000 ;
      RECT 0.000000 156.400000 50.000000 162.400000 ;
      RECT 2.680000 152.400000 50.000000 156.400000 ;
      RECT 0.000000 146.400000 50.000000 152.400000 ;
      RECT 2.680000 142.400000 50.000000 146.400000 ;
      RECT 0.000000 136.400000 50.000000 142.400000 ;
      RECT 2.680000 132.400000 50.000000 136.400000 ;
      RECT 0.000000 126.400000 50.000000 132.400000 ;
      RECT 2.680000 122.400000 50.000000 126.400000 ;
      RECT 0.000000 116.400000 50.000000 122.400000 ;
      RECT 2.680000 112.400000 50.000000 116.400000 ;
      RECT 0.000000 106.400000 50.000000 112.400000 ;
      RECT 2.680000 102.400000 50.000000 106.400000 ;
      RECT 0.000000 96.400000 50.000000 102.400000 ;
      RECT 2.680000 92.400000 50.000000 96.400000 ;
      RECT 0.000000 86.400000 50.000000 92.400000 ;
      RECT 2.680000 82.400000 50.000000 86.400000 ;
      RECT 0.000000 76.400000 50.000000 82.400000 ;
      RECT 2.680000 72.400000 50.000000 76.400000 ;
      RECT 0.000000 66.400000 50.000000 72.400000 ;
      RECT 2.680000 62.400000 50.000000 66.400000 ;
      RECT 0.000000 56.400000 50.000000 62.400000 ;
      RECT 2.680000 52.400000 50.000000 56.400000 ;
      RECT 0.000000 46.400000 50.000000 52.400000 ;
      RECT 2.680000 42.400000 50.000000 46.400000 ;
      RECT 0.000000 36.400000 50.000000 42.400000 ;
      RECT 2.680000 32.400000 50.000000 36.400000 ;
      RECT 0.000000 0.000000 50.000000 32.400000 ;
    LAYER M4 ;
      RECT 36.820000 497.980000 47.480000 500.000000 ;
      RECT 16.820000 497.920000 24.080000 500.000000 ;
      RECT 36.820000 497.480000 50.000000 497.980000 ;
      RECT 29.920000 497.480000 32.780000 500.000000 ;
      RECT 16.820000 497.480000 20.080000 497.920000 ;
      RECT 0.000000 497.480000 12.780000 500.000000 ;
      RECT 29.920000 489.520000 50.000000 497.480000 ;
      RECT 29.920000 485.480000 47.480000 489.520000 ;
      RECT 29.920000 477.020000 50.000000 485.480000 ;
      RECT 29.920000 472.980000 47.480000 477.020000 ;
      RECT 29.920000 464.520000 50.000000 472.980000 ;
      RECT 29.920000 460.480000 47.480000 464.520000 ;
      RECT 29.920000 452.020000 50.000000 460.480000 ;
      RECT 29.920000 447.980000 47.480000 452.020000 ;
      RECT 29.920000 439.520000 50.000000 447.980000 ;
      RECT 29.920000 435.480000 47.480000 439.520000 ;
      RECT 29.920000 427.020000 50.000000 435.480000 ;
      RECT 29.920000 422.980000 47.480000 427.020000 ;
      RECT 29.920000 414.520000 50.000000 422.980000 ;
      RECT 29.920000 410.480000 47.480000 414.520000 ;
      RECT 29.920000 402.020000 50.000000 410.480000 ;
      RECT 29.920000 397.980000 47.480000 402.020000 ;
      RECT 29.920000 389.520000 50.000000 397.980000 ;
      RECT 29.920000 385.480000 47.480000 389.520000 ;
      RECT 29.920000 377.020000 50.000000 385.480000 ;
      RECT 29.920000 372.980000 47.480000 377.020000 ;
      RECT 29.920000 364.520000 50.000000 372.980000 ;
      RECT 29.920000 360.480000 47.480000 364.520000 ;
      RECT 29.920000 352.020000 50.000000 360.480000 ;
      RECT 29.920000 347.980000 47.480000 352.020000 ;
      RECT 29.920000 339.520000 50.000000 347.980000 ;
      RECT 29.920000 335.480000 47.480000 339.520000 ;
      RECT 29.920000 327.020000 50.000000 335.480000 ;
      RECT 29.920000 322.980000 47.480000 327.020000 ;
      RECT 29.920000 314.520000 50.000000 322.980000 ;
      RECT 29.920000 310.480000 47.480000 314.520000 ;
      RECT 29.920000 302.020000 50.000000 310.480000 ;
      RECT 29.920000 297.980000 47.480000 302.020000 ;
      RECT 29.920000 289.520000 50.000000 297.980000 ;
      RECT 29.920000 285.480000 47.480000 289.520000 ;
      RECT 29.920000 277.020000 50.000000 285.480000 ;
      RECT 29.920000 272.980000 47.480000 277.020000 ;
      RECT 29.920000 264.520000 50.000000 272.980000 ;
      RECT 29.920000 260.480000 47.480000 264.520000 ;
      RECT 29.920000 252.020000 50.000000 260.480000 ;
      RECT 29.920000 247.980000 47.480000 252.020000 ;
      RECT 29.920000 239.520000 50.000000 247.980000 ;
      RECT 29.920000 235.480000 47.480000 239.520000 ;
      RECT 29.920000 227.020000 50.000000 235.480000 ;
      RECT 29.920000 222.980000 47.480000 227.020000 ;
      RECT 29.920000 214.520000 50.000000 222.980000 ;
      RECT 29.920000 210.480000 47.480000 214.520000 ;
      RECT 29.920000 202.020000 50.000000 210.480000 ;
      RECT 29.920000 197.980000 47.480000 202.020000 ;
      RECT 29.920000 189.520000 50.000000 197.980000 ;
      RECT 29.920000 185.480000 47.480000 189.520000 ;
      RECT 29.920000 177.020000 50.000000 185.480000 ;
      RECT 29.920000 172.980000 47.480000 177.020000 ;
      RECT 29.920000 164.520000 50.000000 172.980000 ;
      RECT 29.920000 160.480000 47.480000 164.520000 ;
      RECT 29.920000 152.020000 50.000000 160.480000 ;
      RECT 29.920000 147.980000 47.480000 152.020000 ;
      RECT 29.920000 139.520000 50.000000 147.980000 ;
      RECT 29.920000 135.480000 47.480000 139.520000 ;
      RECT 29.920000 127.020000 50.000000 135.480000 ;
      RECT 29.920000 122.980000 47.480000 127.020000 ;
      RECT 29.920000 114.520000 50.000000 122.980000 ;
      RECT 29.920000 110.480000 47.480000 114.520000 ;
      RECT 29.920000 102.020000 50.000000 110.480000 ;
      RECT 29.920000 97.980000 47.480000 102.020000 ;
      RECT 29.920000 89.520000 50.000000 97.980000 ;
      RECT 29.920000 85.480000 47.480000 89.520000 ;
      RECT 29.920000 77.020000 50.000000 85.480000 ;
      RECT 29.920000 72.980000 47.480000 77.020000 ;
      RECT 29.920000 64.520000 50.000000 72.980000 ;
      RECT 29.920000 60.480000 47.480000 64.520000 ;
      RECT 29.920000 52.020000 50.000000 60.480000 ;
      RECT 29.920000 47.980000 47.480000 52.020000 ;
      RECT 29.920000 39.520000 50.000000 47.980000 ;
      RECT 29.920000 35.480000 47.480000 39.520000 ;
      RECT 29.920000 27.020000 50.000000 35.480000 ;
      RECT 29.920000 22.980000 47.480000 27.020000 ;
      RECT 29.920000 14.520000 50.000000 22.980000 ;
      RECT 29.920000 10.480000 47.480000 14.520000 ;
      RECT 0.000000 2.080000 20.080000 497.480000 ;
      RECT 29.920000 2.020000 50.000000 10.480000 ;
      RECT 29.920000 0.000000 47.480000 2.020000 ;
      RECT 0.000000 0.000000 24.080000 2.080000 ;
  END
END wb_controller

END LIBRARY
